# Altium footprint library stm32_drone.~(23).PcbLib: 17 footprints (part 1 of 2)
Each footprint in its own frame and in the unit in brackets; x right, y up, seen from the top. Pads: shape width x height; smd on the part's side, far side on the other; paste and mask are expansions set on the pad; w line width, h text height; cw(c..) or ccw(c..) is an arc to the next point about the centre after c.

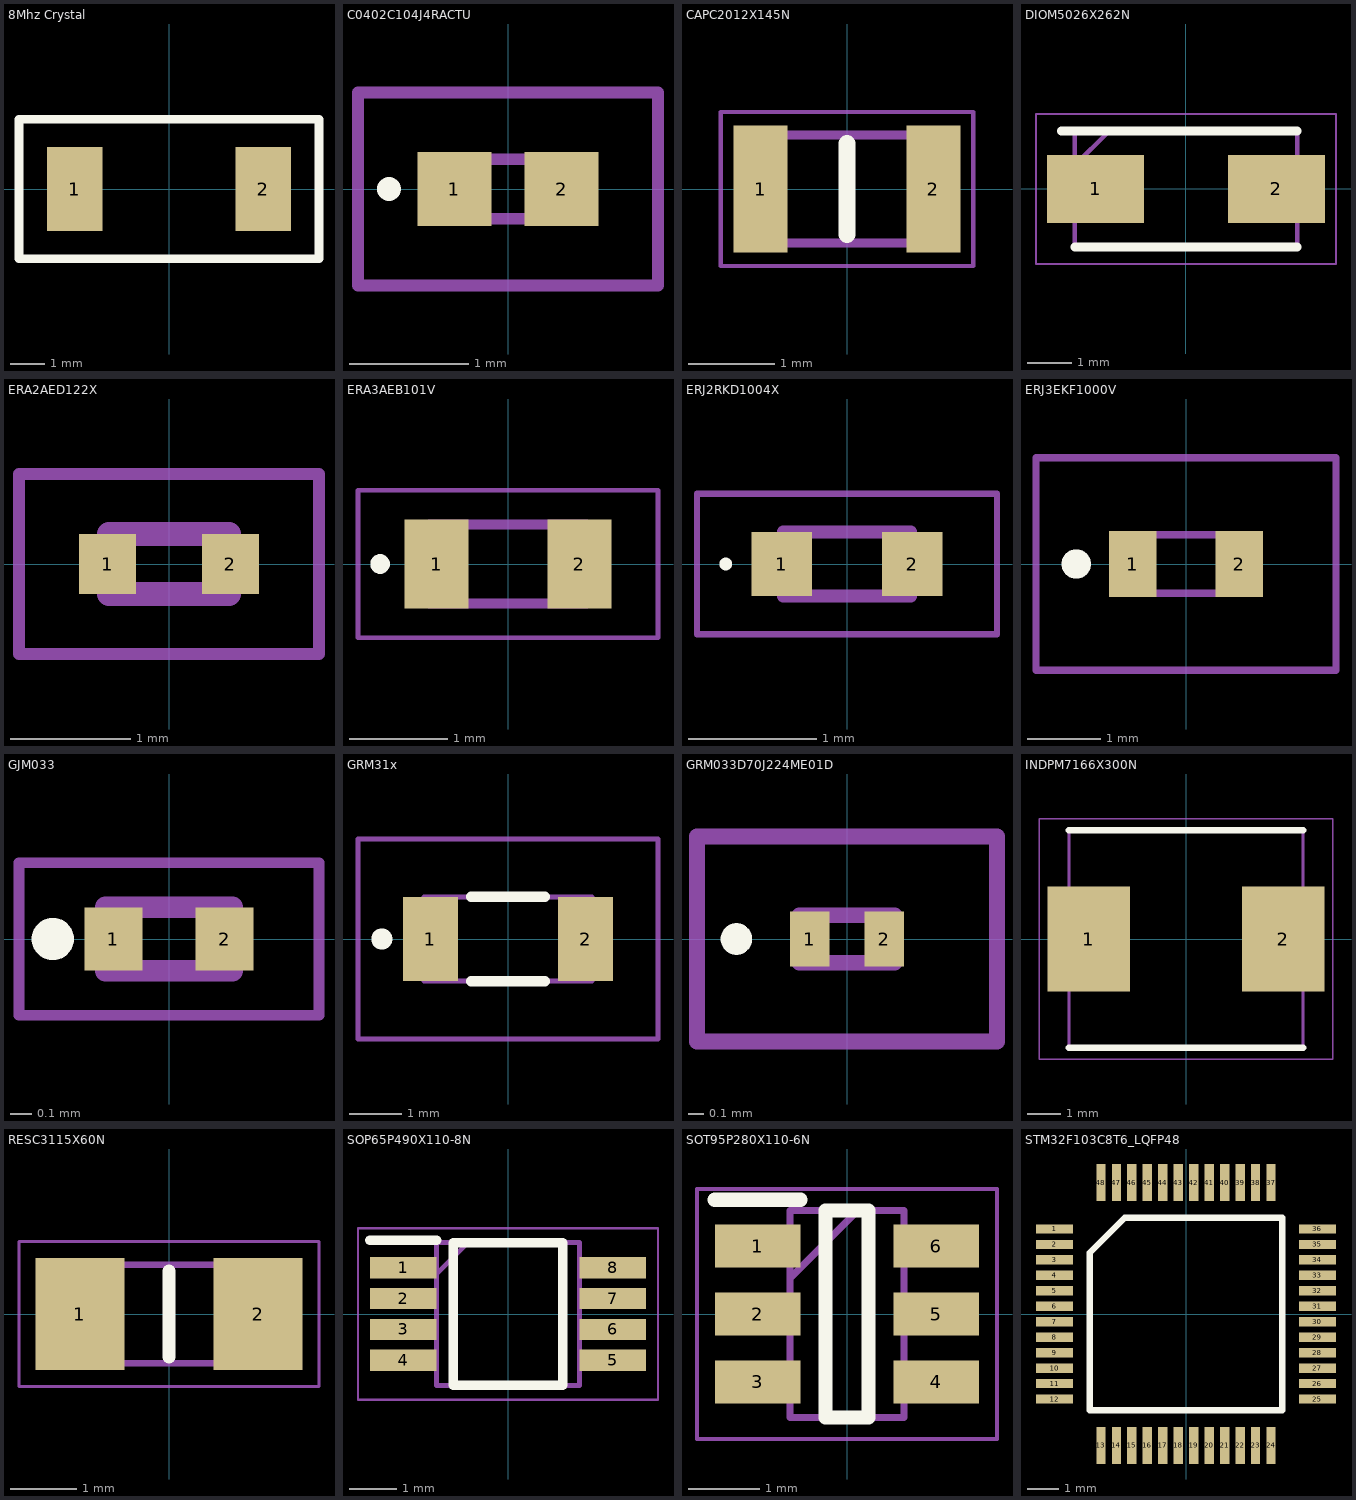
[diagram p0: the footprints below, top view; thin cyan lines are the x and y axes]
## 8Mhz Crystal [mm]
pads (2):
  rect 1.6x2.4 smd: 1(-2.7,0) 2(2.7,0)
Top Overlay:
  lines w0.25: -4.3,-2 4.3,-2 4.3,2 -4.3,2 -4.3,0 -4.3,-2
3D body "XTAL_H130A_RAL.step": height 1.09, standoff 0, extent -2.864,-2.089 2.864,2.089

## C0402C104J4RACTU [mm]
pads (2):
  rect 0.62x0.62 smd: 1(-0.45,0) 2(0.45,0)
Top Overlay:
  lines w0.1: -1,-0.05 cw(c-1,0) -1,0.05 cw(c-1,0) -1,-0.05
Mechanical 13:
  lines w0.1: -0.5,-0.25 0.5,-0.25 0.5,0.25 -0.5,0.25 -0.5,-0.25
Mechanical 15:
  lines w0.1: -1.26,-0.81 1.26,-0.81 1.26,0.81 -1.26,0.81 -1.26,-0.81
3D body "C0402C102J5GECTU.stp": height 0.55, standoff 0, extent -0.52,-0.28 0.53,0.27

## CAPC2012X145N [mm]
pads (2):
  rect 0.62x1.47 smd: 1(-1,0) 2(1,0)
Top Overlay:
  lines w0.2: 0,-0.525 0,0.525
Mechanical 13:
  lines w0.1: -1,-0.625 1,-0.625 1,0.625 -1,0.625 -1,-0.625
Mechanical 15:
  lines w0.05: -1.46,-0.89 1.46,-0.89 1.46,0.89 -1.46,0.89 -1.46,-0.89
3D body "C2012X5R1V226M125AC.stp": height 1.25, standoff 0, extent -1,-0.8 1,0.8

## DIOM5026X262N [mm]
pads (2):
  rect 2.2x1.55 smd: 1(-2.05,0) 2(2.05,0)
Top Overlay:
  lines w0.2: -2.825,1.312 2.52,1.312 ; -2.52,-1.312 2.52,-1.312
Mechanical 13:
  lines w0.1: -2.52,0.538 -1.745,1.312 ; -2.52,-1.312 -2.52,1.312 2.52,1.312 2.52,-1.312 -2.52,-1.312
Mechanical 15:
  lines w0.05: -3.4,-1.7 -3.4,1.7 3.4,1.7 3.4,-1.7 -3.4,-1.7
3D body "SS14.stp": height 2.62, standoff 0, extent -2.52,-1.312 2.52,1.312

## ERA2AED122X [mm]
pads (2):
  rect 0.475x0.5 smd: 1(-0.512,0) 2(0.512,0)
Mechanical 13:
  lines w0.2: -0.5,-0.25 0.5,-0.25 0.5,0.25 -0.5,0.25 -0.5,-0.25
Mechanical 15:
  lines w0.1: -1.25,-0.75 1.25,-0.75 1.25,0.75 -1.25,0.75 -1.25,-0.75
3D body "ERA-2AEB4990X.stp": height 0.35, standoff 0, extent -0.5,-0.25 0.5,0.25
3D body "0402_PAN.step": height 0.41, standoff 0, extent -0.546,-0.305 0.546,0.305

## ERA3AEB101V [mm]
pads (2):
  rect 0.65x0.9 smd: 1(-0.725,0) 2(0.725,0)
Top Overlay:
  lines w0.1: -1.3,-0.05 cw(c-1.3,0) -1.3,0.05 cw(c-1.3,0) -1.3,-0.05
Mechanical 13:
  lines w0.1: -0.8,-0.4 0.8,-0.4 0.8,0.4 -0.8,0.4 -0.8,-0.4
Mechanical 15:
  lines w0.05: -1.525,-0.75 1.525,-0.75 1.525,0.75 -1.525,0.75 -1.525,-0.75
3D body "ERA-3AEB333V.stp": height 0.45, standoff 0, extent -0.8,-0.4 0.8,0.4

## ERJ2RKD1004X [mm]
pads (2):
  rect 0.475x0.5 smd: 1(-0.512,0) 2(0.512,0)
Top Overlay:
  lines w0.05: -0.95,-0.025 cw(c-0.95,0) -0.95,0.025 cw(c-0.95,0) -0.95,-0.025
Mechanical 13:
  lines w0.1: -0.5,-0.25 0.5,-0.25 0.5,0.25 -0.5,0.25 -0.5,-0.25
Mechanical 15:
  lines w0.05: -1.175,-0.55 1.175,-0.55 1.175,0.55 -1.175,0.55 -1.175,-0.55
3D body "ERJ-2RKF2002X.stp": height 0.35, standoff 0, extent -0.5,-0.25 0.5,0.25

## ERJ3EKF1000V [mm]
pads (2):
  rect 0.65x0.9 smd: 1(-0.725,0) 2(0.725,0)
Top Overlay:
  lines w0.2: -1.5,-0.1 cw(c-1.5,0) -1.5,0.1 cw(c-1.5,0) -1.5,-0.1
Mechanical 13:
  lines w0.1: -0.8,-0.4 0.8,-0.4 0.8,0.4 -0.8,0.4 -0.8,-0.4
Mechanical 15:
  lines w0.1: -2.05,-1.45 2.05,-1.45 2.05,1.45 -2.05,1.45 -2.05,-1.45
3D body "ERJ-3GEYJ244V.stp": height 0.45, standoff 0, extent -0.8,-0.4 0.8,0.4

## GJM033 [mm]
pads (2):
  rect 0.275x0.3 smd: 1(-0.263,0) 2(0.263,0)
Top Overlay:
  lines w0.1: -0.55,-0.05 cw(c-0.55,0) -0.55,0.05 cw(c-0.55,0) -0.55,-0.05
Mechanical 13:
  lines w0.1: -0.3,-0.15 0.3,-0.15 0.3,0.15 -0.3,0.15 -0.3,-0.15
Mechanical 15:
  lines w0.05: -0.71,-0.36 0.71,-0.36 0.71,0.36 -0.71,0.36 -0.71,-0.36
3D body "GJM0335C1E2R0BB01D.stp": height 0.33, standoff 0, extent -0.3,-0.15 0.3,0.15

## GRM31x [mm]
pads (2):
  rect 1.05x1.6 smd: 1(-1.475,0) 2(1.475,0)
Top Overlay:
  lines w0.2: -0.7,-0.8 0.7,-0.8 ; -0.7,0.8 0.7,0.8 ; -2.4,-0.1 ccw(c-2.4,0) -2.4,0.1 ccw(c-2.4,0) -2.4,-0.1
Mechanical 13:
  lines w0.1: -1.6,-0.8 -1.6,0.8 1.6,0.8 1.6,-0.8 -1.6,-0.8
Mechanical 15:
  lines w0.1: -2.854,-1.902 -2.854,1.902 2.854,1.902 2.854,-1.902 -2.854,-1.902
3D body "GRM31CR60J107MEA8K.stp": height 1, standoff 0, extent -1.6,-0.8 1.6,0.8

## GRM033D70J224ME01D [mm]
pads (2):
  rect 0.25x0.35 smd: 1(-0.237,0) 2(0.237,0)
Top Overlay:
  lines w0.1: -0.7,-0.05 cw(c-0.7,0) -0.7,0.05 cw(c-0.7,0) -0.7,-0.05
Mechanical 13:
  lines w0.1: -0.3,-0.15 0.3,-0.15 0.3,0.15 -0.3,0.15 -0.3,-0.15
Mechanical 15:
  lines w0.1: -0.95,-0.65 0.95,-0.65 0.95,0.65 -0.95,0.65 -0.95,-0.65
3D body "GRM033C80J104KE15D.stp": height 0.3, standoff 0, extent -0.3,-0.15 0.3,0.15

## INDPM7166X300N [mm]
pads (2):
  rect 2.5x3.2 smd: 1(-2.95,0) 2(2.95,0)
Top Overlay:
  lines w0.2: -3.55,-3.3 3.55,-3.3 ; -3.55,3.3 3.55,3.3
Mechanical 13:
  lines w0.1: -3.55,-3.3 -3.55,3.3 3.55,3.3 3.55,-3.3 -3.55,-3.3
Mechanical 15:
  lines w0.05: -4.45,-3.65 -4.45,3.65 4.45,3.65 4.45,-3.65 -4.45,-3.65
3D body "ECS-MPIL0630-220MC.stp": height 3, standoff 0, extent -3.55,-3.3 3.55,3.3

## RESC3115X60N [mm]
pads (2):
  rect 1.35x1.7 smd: 1(-1.35,0) 2(1.35,0)
Top Overlay:
  lines w0.2: 0,-0.65 0,0.65
Mechanical 13:
  lines w0.1: -1.55,-0.75 -1.55,0.75 1.55,0.75 1.55,-0.75 -1.55,-0.75
Mechanical 15:
  lines w0.05: -2.275,-1.1 -2.275,1.1 2.275,1.1 2.275,-1.1 -2.275,-1.1
3D body "RNCP1206FTD10K0.stp": height 0.5, standoff 0, extent -1.554,-0.746 1.546,0.754

## SOP65P490X110-8N [mm]
pads (8):
  rect 1.4x0.45 smd: 1(-2.2,0.975) 2(-2.2,0.325) 3(-2.2,-0.325) 4(-2.2,-0.975) 5(2.2,-0.975) 6(2.2,-0.325) 7(2.2,0.325) 8(2.2,0.975)
Top Overlay:
  lines w0.2: -2.9,1.55 -1.5,1.55 ; -1.15,-1.5 -1.15,1.5 1.15,1.5 1.15,-1.5 -1.15,-1.5
Mechanical 13:
  lines w0.1: -1.5,0.85 -0.85,1.5 ; -1.5,-1.5 -1.5,1.5 1.5,1.5 1.5,-1.5 -1.5,-1.5
Mechanical 15:
  lines w0.05: -3.15,-1.8 -3.15,1.8 3.15,1.8 3.15,-1.8 -3.15,-1.8
3D body "LM3485MMX_NOPB.stp": height 1.1, standoff 0, extent -2.451,-1.499 2.451,1.499

## SOT95P280X110-6N [mm]
pads (6):
  rect 1.2x0.6 smd: 1(-1.25,0.95) 2(-1.25,0) 3(-1.25,-0.95) 4(1.25,-0.95) 5(1.25,0) 6(1.25,0.95)
Top Overlay:
  lines w0.2: -1.85,1.6 -0.65,1.6 ; -0.3,-1.45 0.3,-1.45 0.3,1.45 -0.3,1.45 -0.3,-1.45
Mechanical 13:
  lines w0.1: -0.8,0.5 0.15,1.45 ; -0.8,-1.45 0.8,-1.45 0.8,1.45 -0.8,1.45 -0.8,-1.45
Mechanical 15:
  lines w0.05: -2.1,-1.75 2.1,-1.75 2.1,1.75 -2.1,1.75 -2.1,-1.75
3D body "FDC5614P.stp": height 1.1, standoff 0, extent -1.4,-1.45 1.4,1.45

## STM32F103C8T6_LQFP48 [mm]
pads (48):
  rect 1.2x0.3 smd mask+0.05: 1(-4.25,2.75) 2(-4.25,2.25) 3(-4.25,1.75) 4(-4.25,1.25) 5(-4.25,0.75) 6(-4.25,0.25) 7(-4.25,-0.25) 8(-4.25,-0.75) 9(-4.25,-1.25) 10(-4.25,-1.75) 11(-4.25,-2.25) 12(-4.25,-2.75) 25(4.25,-2.75) 26(4.25,-2.25) 27(4.25,-1.75) 28(4.25,-1.25) 29(4.25,-0.75) 30(4.25,-0.25) 31(4.25,0.25) 32(4.25,0.75) 33(4.25,1.25) 34(4.25,1.75) 35(4.25,2.25) 36(4.25,2.75)
  rect 0.3x1.2 smd mask+0.05: 13(-2.75,-4.25) 14(-2.25,-4.25) 15(-1.75,-4.25) 16(-1.25,-4.25) 17(-0.75,-4.25) 18(-0.25,-4.25) 19(0.25,-4.25) 20(0.75,-4.25) 21(1.25,-4.25) 22(1.75,-4.25) 23(2.25,-4.25) 24(2.75,-4.25) 37(2.75,4.25) 38(2.25,4.25) 39(1.75,4.25) 40(1.25,4.25) 41(0.75,4.25) 42(0.25,4.25) 43(-0.25,4.25) 44(-0.75,4.25) 45(-1.25,4.25) 46(-1.75,4.25) 47(-2.25,4.25) 48(-2.75,4.25)
Top Overlay:
  lines w0.2: -3.115,-3.115 3.115,-3.115 3.115,3.115 -1.98,3.115 -3.115,1.98 -3.115,-3.115
3D body "LQFP48_STM.step": height 1.6, standoff 0, extent -4.597,-4.597 4.597,4.597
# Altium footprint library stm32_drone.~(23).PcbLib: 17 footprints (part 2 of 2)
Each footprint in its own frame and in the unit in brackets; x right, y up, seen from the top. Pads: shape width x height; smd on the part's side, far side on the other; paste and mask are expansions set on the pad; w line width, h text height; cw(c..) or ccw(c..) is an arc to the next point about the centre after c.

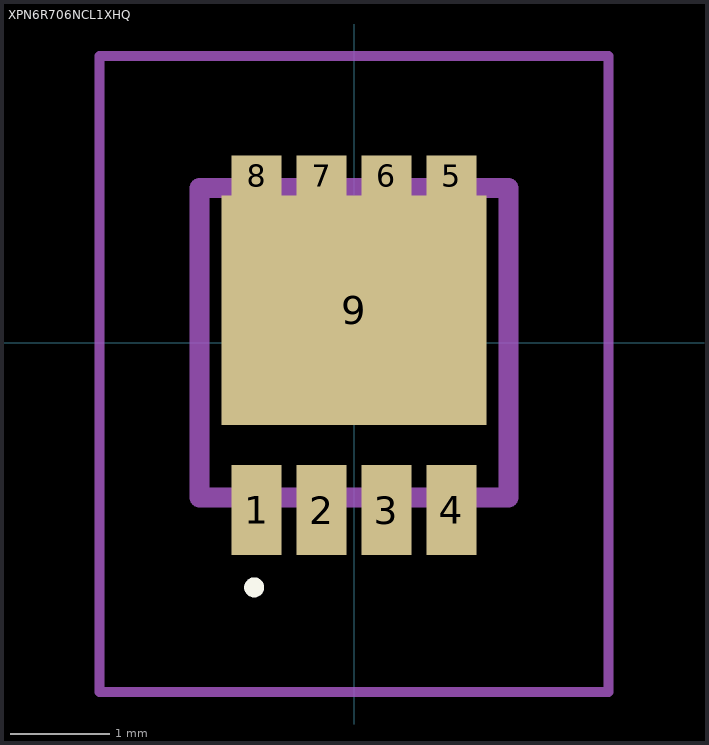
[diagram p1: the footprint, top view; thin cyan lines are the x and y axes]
## XPN6R706NCL1XHQ [mm]
pads (9):
  rect 0.5x0.9 smd: 1(-0.975,-1.675) 2(-0.325,-1.675) 3(0.325,-1.675) 4(0.975,-1.675)
  rect 0.5x0.4 smd: 5(0.975,1.675) 6(0.325,1.675) 7(-0.325,1.675) 8(-0.975,1.675)
  rect 2.65x2.3 smd: 9(0,0.325)
Top Overlay:
  lines w0.1: -1,-2.5 cw(c-1,-2.45) -1,-2.4 cw(c-1,-2.45) -1,-2.5
Mechanical 13:
  lines w0.2: -1.55,-1.55 1.55,-1.55 1.55,1.55 -1.55,1.55 -1.55,-1.55
Mechanical 15:
  lines w0.1: -2.55,-3.5 2.55,-3.5 2.55,2.875 -2.55,2.875 -2.55,-3.5
3D body "XPN6R706NC,L1XHQ.stp": height 1, standoff 0, extent -1.55,-2.075 1.55,1.835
